One B-rep face of a CAD part: STEP entity #554.
In plain terms, the planar face has unit normal (1, 0, 0).
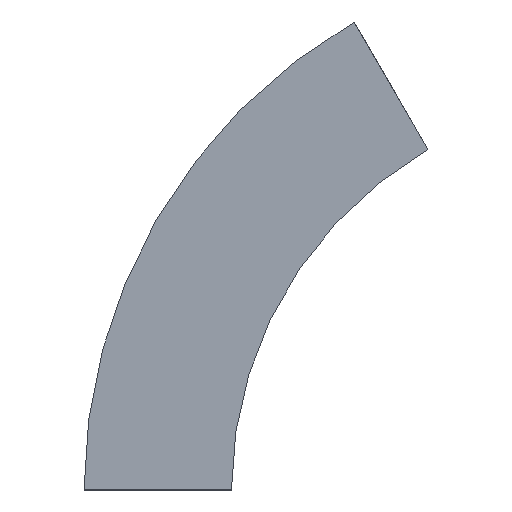
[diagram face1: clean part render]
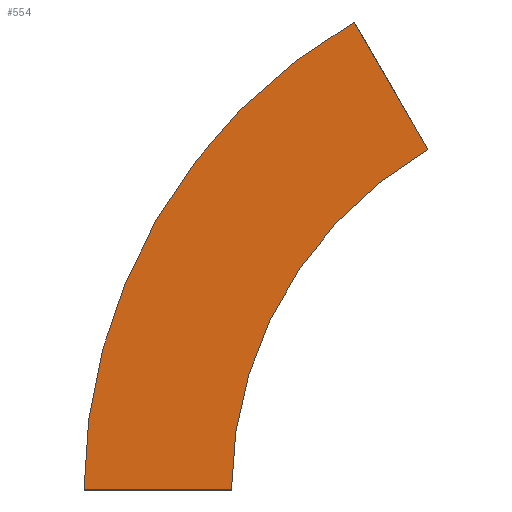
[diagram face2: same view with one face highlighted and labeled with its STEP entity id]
Its self-contained STEP definition (entity closure, numbers rounded to 3 decimals):
#26 = DIRECTION ( 'NONE',  ( 0., 1., 0. ) ) ;
#27 = EDGE_LOOP ( 'NONE', ( #137, #348, #203, #257 ) ) ;
#33 = DIRECTION ( 'NONE',  ( 1., 0., 0. ) ) ;
#57 = VERTEX_POINT ( 'NONE', #217 ) ;
#78 = PLANE ( 'NONE',  #231 ) ;
#83 = DIRECTION ( 'NONE',  ( 0., 0., -1. ) ) ;
#85 = CARTESIAN_POINT ( 'NONE',  ( 0., -93.75, 357.235 ) ) ;
#99 = CARTESIAN_POINT ( 'NONE',  ( 0., -150., 259.808 ) ) ;
#110 = EDGE_CURVE ( 'NONE', #250, #456, #376, .T. ) ;
#116 = CIRCLE ( 'NONE', #448, 300. ) ;
#122 = VECTOR ( 'NONE', #26, 1000. ) ;
#132 = EDGE_CURVE ( 'NONE', #230, #250, #437, .T. ) ;
#134 = CARTESIAN_POINT ( 'NONE',  ( 0., 0., 0. ) ) ;
#137 = ORIENTED_EDGE ( 'NONE', *, *, #110, .T. ) ;
#203 = ORIENTED_EDGE ( 'NONE', *, *, #209, .F. ) ;
#209 = EDGE_CURVE ( 'NONE', #230, #57, #116, .T. ) ;
#217 = CARTESIAN_POINT ( 'NONE',  ( 0., -150., 259.808 ) ) ;
#223 = DIRECTION ( 'NONE',  ( 0., 0.5, 0.866 ) ) ;
#230 = VERTEX_POINT ( 'NONE', #134 ) ;
#231 = AXIS2_PLACEMENT_3D ( 'NONE', #245, #289, #83 ) ;
#245 = CARTESIAN_POINT ( 'NONE',  ( 0., 0., 0. ) ) ;
#249 = FACE_OUTER_BOUND ( 'NONE', #27, .T. ) ;
#250 = VERTEX_POINT ( 'NONE', #506 ) ;
#257 = ORIENTED_EDGE ( 'NONE', *, *, #132, .T. ) ;
#281 = EDGE_CURVE ( 'NONE', #57, #456, #507, .T. ) ;
#289 = DIRECTION ( 'NONE',  ( 1., 0., 0. ) ) ;
#291 = CARTESIAN_POINT ( 'NONE',  ( 0., 0., 0. ) ) ;
#348 = ORIENTED_EDGE ( 'NONE', *, *, #281, .F. ) ;
#355 = CARTESIAN_POINT ( 'NONE',  ( 0., -300., 0. ) ) ;
#365 = AXIS2_PLACEMENT_3D ( 'NONE', #561, #33, #495 ) ;
#376 = CIRCLE ( 'NONE', #365, 412.5 ) ;
#404 = DIRECTION ( 'NONE',  ( 1., 0., 0. ) ) ;
#424 = VECTOR ( 'NONE', #223, 1000. ) ;
#437 = LINE ( 'NONE', #291, #122 ) ;
#448 = AXIS2_PLACEMENT_3D ( 'NONE', #355, #404, #540 ) ;
#456 = VERTEX_POINT ( 'NONE', #85 ) ;
#495 = DIRECTION ( 'NONE',  ( 0., 1., 0. ) ) ;
#506 = CARTESIAN_POINT ( 'NONE',  ( 0., 112.5, 0. ) ) ;
#507 = LINE ( 'NONE', #99, #424 ) ;
#540 = DIRECTION ( 'NONE',  ( 0., 1., 0. ) ) ;
#554 = ADVANCED_FACE ( 'NONE', ( #249 ), #78, .T. ) ;
#561 = CARTESIAN_POINT ( 'NONE',  ( 0., -300., 0. ) ) ;
